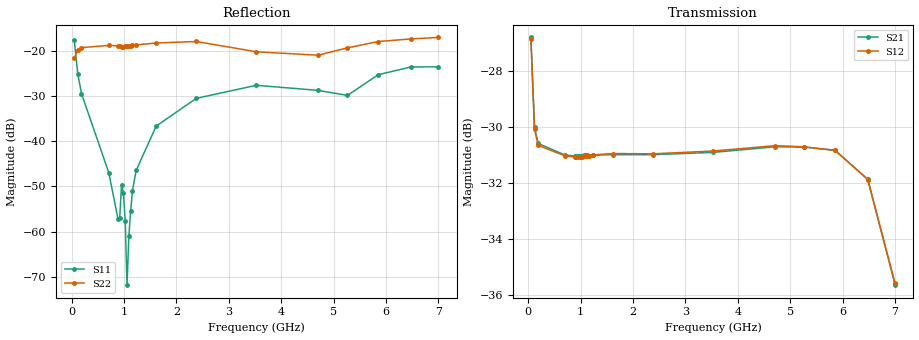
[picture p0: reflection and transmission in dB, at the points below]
! Integrated Device Technology
! Corporate Headquarters
! 6024 Silver Creek Valley Road
! San Jose, CA 95138  USA
! Phone:  1-408-284-8200
! Toll Free:  1-800-223-1366
! Webpage:  http://www.idt.com/
! Timing and RF Division
! 515 Groton Road, Suite 102
! Westford, MA 01886-6024
! Device:  F2258
! Description: Voltage Variable RF Attenuator
! Frequency:  50.0 -  6000.00 MHz
! Package:  3x3 mm Thin QFN Plastic Package: 16 pin
! Ports:  2 RF, 2 DC
!  Pin  1  = NC
!  Pin  2  = NC
!  Pin  3  = RF2  = Port 2
!  Pin  4  = GND
!  Pin  5  = Vdd
!  Pin  6  = NC
!  Pin  7  = VCTRL
!  Pin  8  = NC
!  Pin  9  = GND
!  Pin 10  = RF1  = Port 1
!  Pin 11  = NC
!  Pin 12  = NC
!  Pin 13  = NC
!  Pin 14  = NC
!  Pin 15  = NC
!  Pin 16  = NC
! Vcntrl:  1.700 Volts
! Vdd:  +3.300 Volts
! Current:  1.157 mA
! Data:  The device was measured on a the F2258 evaluation board which has
!  individual transmission lines to the RF pins.  Data was collected
!  using a calibrated network analyzer.  The evaluation board was
!  de-embedded using a TRL calibration technique.
!  The reference plane is the edge of the package pin.
! Misc:  SN 10
!  Action Tracker AT0285
! Date Measured:  2014-12-10
! Date:  2016-01-13  MJV
! Note:
!  Integrated Device Technology supplies this data as a sample of measured
!  data at the package pin for this product.  Your particular data for this
!  product may vary.
!  Data was taken at 25 degrees C.
!  Integrated Device Technology reserves the right to change this data at anytime.
!Freq_(GHz)  S11M_(dB)  S11P_(deg)  S21M_(dB)  S21P_(deg)  S12M_(dB)  S12P_(deg)  S22M_(dB)  S22P_(deg)
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# GHz S dB R 50
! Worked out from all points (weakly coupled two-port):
!   201 points, 50 MHz to 7 GHz, reference 50 ohm
!   highest |S21| = -26.81 dB at 50 MHz (marker M1); lowest = -35.6 dB at 7 GHz (marker M2)
!   lowest |S11| = -71.9 dB at 1.058 GHz (marker M3), VSWR 1.00, Z = 50 + j0.0223 ohm
!   |S11| at or under -10 dB: start of sweep to end of sweep
!   |S22| runs from -21.7 to -17.0 dB; largest |S21 - S12| = 0.00025
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0.05  -17.52 -110.2  -26.81 -52.7  -26.85 -52.9  -21.57 -52.7
0.1195  -25.10 -105.5  -30.02 -28.0  -30.08 -28.1  -19.66 -15.3
0.189  -29.43 -107.4  -30.59 -19.3  -30.66 -19.3  -19.23 -9.9
0.71025  -46.96 -124.9  -31.01 -10.4  -31.04 -10.4  -18.74 -8.3
0.884  -57.12 168.3  -31.03 -10.7  -31.07 -10.6  -18.82 -10.5
0.91875  -56.96 141.4  -31.02 -10.8  -31.06 -10.8  -18.82 -10.9
0.9535  -49.58 -151.7  -31.02 -10.8  -31.07 -10.8  -19.06 -10.3
0.98825  -51.40 -164.8  -31.03 -10.9  -31.07 -10.9  -19.05 -11.0
1.023  -57.56 -175.8  -31.03 -11.0  -31.07 -11.0  -18.96 -11.4
1.05775  -71.87 119.1  -31.01 -11.1  -31.05 -11.1  -18.88 -11.6
1.0925  -61.08 61.1  -31.00 -11.3  -31.05 -11.2  -18.87 -11.9
1.12725  -55.40 55.8  -31.00 -11.4  -31.04 -11.4  -18.80 -12.4
1.162  -50.92 46.8  -31.02 -11.6  -31.04 -11.6  -18.75 -12.6
1.2315  -46.46 33.9  -31.01 -12.0  -31.00 -12.0  -18.62 -13.3
1.61375  -36.63 29.1  -30.99 -14.8  -30.95 -14.8  -18.20 -16.8
2.37825  -30.48 46.1  -30.99 -20.5  -30.96 -20.6  -17.87 -22.8
3.525  -27.58 90.7  -30.91 -29.9  -30.86 -29.9  -20.15 -36.5
4.7065  -28.71 95.0  -30.71 -40.9  -30.67 -41.0  -20.91 -60.8
5.2625  -29.82 52.8  -30.72 -47.1  -30.71 -47.2  -19.28 -63.2
5.85325  -25.22 28.9  -30.83 -56.2  -30.84 -56.1  -17.88 -62.7
6.47875  -23.51 40.7  -31.87 -69.1  -31.88 -69.2  -17.30 -78.9
7  -23.49 83.9  -35.64 -70.0  -35.58 -70.0  -16.96 -125.3
